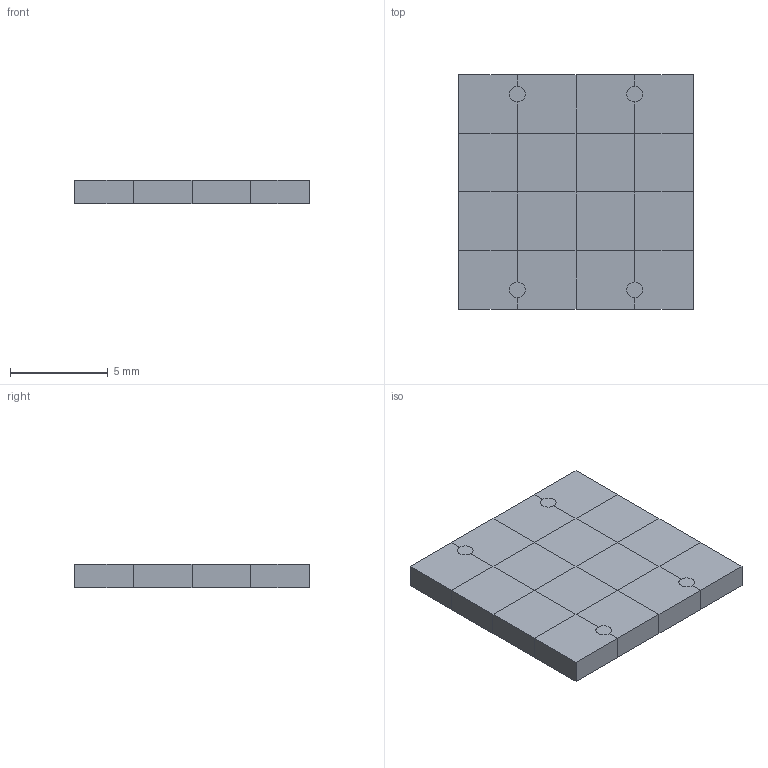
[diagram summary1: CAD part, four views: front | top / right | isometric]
STEP (ISO 10303-21) file: header records copied from the file, then geometry measured from it (millimetres).
FILE_DESCRIPTION(('Open CASCADE Model'),'2;1');
FILE_NAME('Open CASCADE Shape Model','2026-11-20T12:54:42',('Author'),( 'Open CASCADE'),'Open CASCADE STEP processor 7.9','Open CASCADE 7.9' ,'Unknown');
FILE_SCHEMA(('AUTOMOTIVE_DESIGN { 1 0 10303 214 1 1 1 1 }'));
Length unit declared in the file: millimetre
Products named in the file (3): manifold_AD_13-14_2; fluid; solid
Assembly tree (2 placements, depth 2):
  manifold_AD_13-14_2
    fluid
    solid
Bounding box: 12 x 12 x 1.2 mm (x, y, z)
Volume: 172.8 mm3; surface area: 1521.5 mm2
Topology: 2 solids, 2 shells, 1568 faces, 5808 edges, 3138 vertices
Faces by surface type: plane 1560, cylinder 8
Full cylindrical faces by diameter (mm): 0.8 x8
Entity records: 135214 total; most frequent: CARTESIAN_POINT 22181, DIRECTION 20582, LINE 17376, VECTOR 17376, ORIENTED_EDGE 11616, PCURVE 11616, DEFINITIONAL_REPRESENTATION 11616, EDGE_CURVE 5808
One B-rep face of a CAD part: STEP entity #72534.
In plain terms, the planar face has unit normal (0, 0, 1).
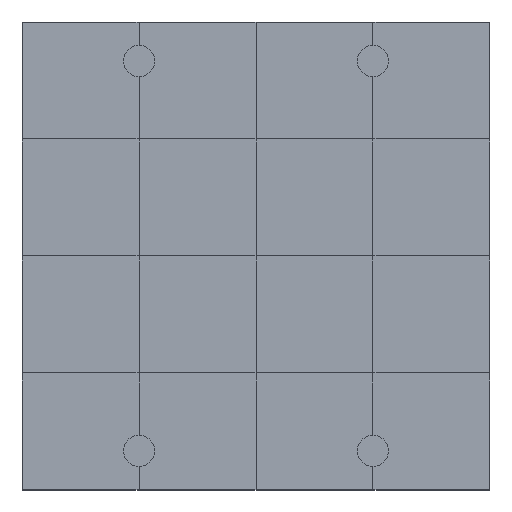
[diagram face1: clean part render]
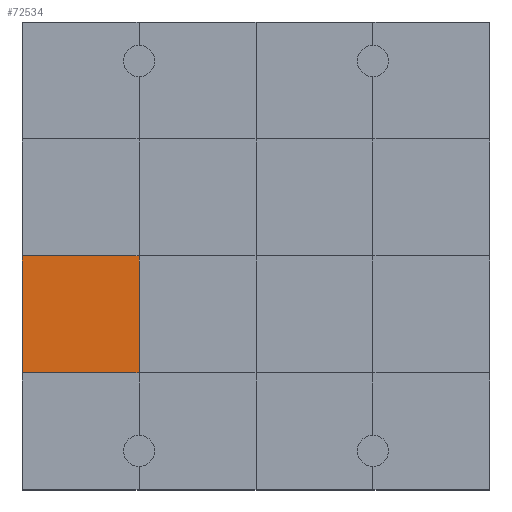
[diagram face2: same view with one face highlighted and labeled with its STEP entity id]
Its self-contained STEP definition (entity closure, numbers rounded to 3 decimals):
#72084 = VERTEX_POINT('',#72085);
#72085 = CARTESIAN_POINT('',(0.,3.,1.2));
#72099 = PLANE('',#72100);
#72100 = AXIS2_PLACEMENT_3D('',#72101,#72102,#72103);
#72101 = CARTESIAN_POINT('',(0.,3.,0.));
#72102 = DIRECTION('',(1.,0.,-0.));
#72103 = DIRECTION('',(0.,0.,1.));
#72125 = PLANE('',#72126);
#72126 = AXIS2_PLACEMENT_3D('',#72127,#72128,#72129);
#72127 = CARTESIAN_POINT('',(0.,0.,1.2));
#72128 = DIRECTION('',(0.,0.,1.));
#72129 = DIRECTION('',(1.,0.,-0.));
#72276 = VERTEX_POINT('',#72277);
#72277 = CARTESIAN_POINT('',(3.,3.,1.2));
#72298 = EDGE_CURVE('',#72084,#72276,#72299,.T.);
#72299 = SURFACE_CURVE('',#72300,(#72304,#72311),.PCURVE_S1.);
#72300 = LINE('',#72301,#72302);
#72301 = CARTESIAN_POINT('',(0.,3.,1.2));
#72302 = VECTOR('',#72303,1.);
#72303 = DIRECTION('',(1.,0.,-0.));
#72304 = PCURVE('',#72125,#72305);
#72305 = DEFINITIONAL_REPRESENTATION('',(#72306),#72310);
#72306 = LINE('',#72307,#72308);
#72307 = CARTESIAN_POINT('',(0.,3.));
#72308 = VECTOR('',#72309,1.);
#72309 = DIRECTION('',(1.,0.));
#72310 = ( GEOMETRIC_REPRESENTATION_CONTEXT(2) 
PARAMETRIC_REPRESENTATION_CONTEXT() REPRESENTATION_CONTEXT('2D SPACE',''
  ) );
#72311 = PCURVE('',#72312,#72317);
#72312 = PLANE('',#72313);
#72313 = AXIS2_PLACEMENT_3D('',#72314,#72315,#72316);
#72314 = CARTESIAN_POINT('',(0.,3.,1.2));
#72315 = DIRECTION('',(0.,0.,1.));
#72316 = DIRECTION('',(1.,0.,-0.));
#72317 = DEFINITIONAL_REPRESENTATION('',(#72318),#72322);
#72318 = LINE('',#72319,#72320);
#72319 = CARTESIAN_POINT('',(0.,0.));
#72320 = VECTOR('',#72321,1.);
#72321 = DIRECTION('',(1.,0.));
#72322 = ( GEOMETRIC_REPRESENTATION_CONTEXT(2) 
PARAMETRIC_REPRESENTATION_CONTEXT() REPRESENTATION_CONTEXT('2D SPACE',''
  ) );
#72357 = VERTEX_POINT('',#72358);
#72358 = CARTESIAN_POINT('',(0.,6.,1.2));
#72384 = EDGE_CURVE('',#72084,#72357,#72385,.T.);
#72385 = SURFACE_CURVE('',#72386,(#72390,#72397),.PCURVE_S1.);
#72386 = LINE('',#72387,#72388);
#72387 = CARTESIAN_POINT('',(0.,3.,1.2));
#72388 = VECTOR('',#72389,1.);
#72389 = DIRECTION('',(-0.,1.,0.));
#72390 = PCURVE('',#72099,#72391);
#72391 = DEFINITIONAL_REPRESENTATION('',(#72392),#72396);
#72392 = LINE('',#72393,#72394);
#72393 = CARTESIAN_POINT('',(1.2,0.));
#72394 = VECTOR('',#72395,1.);
#72395 = DIRECTION('',(0.,-1.));
#72396 = ( GEOMETRIC_REPRESENTATION_CONTEXT(2) 
PARAMETRIC_REPRESENTATION_CONTEXT() REPRESENTATION_CONTEXT('2D SPACE',''
  ) );
#72397 = PCURVE('',#72312,#72398);
#72398 = DEFINITIONAL_REPRESENTATION('',(#72399),#72403);
#72399 = LINE('',#72400,#72401);
#72400 = CARTESIAN_POINT('',(0.,0.));
#72401 = VECTOR('',#72402,1.);
#72402 = DIRECTION('',(0.,1.));
#72403 = ( GEOMETRIC_REPRESENTATION_CONTEXT(2) 
PARAMETRIC_REPRESENTATION_CONTEXT() REPRESENTATION_CONTEXT('2D SPACE',''
  ) );
#72534 = ADVANCED_FACE('',(#72535),#72312,.T.);
#72535 = FACE_BOUND('',#72536,.T.);
#72536 = EDGE_LOOP('',(#72537,#72538,#72539,#72567));
#72537 = ORIENTED_EDGE('',*,*,#72384,.F.);
#72538 = ORIENTED_EDGE('',*,*,#72298,.T.);
#72539 = ORIENTED_EDGE('',*,*,#72540,.T.);
#72540 = EDGE_CURVE('',#72276,#72541,#72543,.T.);
#72541 = VERTEX_POINT('',#72542);
#72542 = CARTESIAN_POINT('',(3.,6.,1.2));
#72543 = SURFACE_CURVE('',#72544,(#72548,#72555),.PCURVE_S1.);
#72544 = LINE('',#72545,#72546);
#72545 = CARTESIAN_POINT('',(3.,3.,1.2));
#72546 = VECTOR('',#72547,1.);
#72547 = DIRECTION('',(-0.,1.,0.));
#72548 = PCURVE('',#72312,#72549);
#72549 = DEFINITIONAL_REPRESENTATION('',(#72550),#72554);
#72550 = LINE('',#72551,#72552);
#72551 = CARTESIAN_POINT('',(3.,0.));
#72552 = VECTOR('',#72553,1.);
#72553 = DIRECTION('',(0.,1.));
#72554 = ( GEOMETRIC_REPRESENTATION_CONTEXT(2) 
PARAMETRIC_REPRESENTATION_CONTEXT() REPRESENTATION_CONTEXT('2D SPACE',''
  ) );
#72555 = PCURVE('',#72556,#72561);
#72556 = PLANE('',#72557);
#72557 = AXIS2_PLACEMENT_3D('',#72558,#72559,#72560);
#72558 = CARTESIAN_POINT('',(3.,3.,1.2));
#72559 = DIRECTION('',(0.,0.,1.));
#72560 = DIRECTION('',(1.,0.,-0.));
#72561 = DEFINITIONAL_REPRESENTATION('',(#72562),#72566);
#72562 = LINE('',#72563,#72564);
#72563 = CARTESIAN_POINT('',(0.,0.));
#72564 = VECTOR('',#72565,1.);
#72565 = DIRECTION('',(0.,1.));
#72566 = ( GEOMETRIC_REPRESENTATION_CONTEXT(2) 
PARAMETRIC_REPRESENTATION_CONTEXT() REPRESENTATION_CONTEXT('2D SPACE',''
  ) );
#72567 = ORIENTED_EDGE('',*,*,#72568,.F.);
#72568 = EDGE_CURVE('',#72357,#72541,#72569,.T.);
#72569 = SURFACE_CURVE('',#72570,(#72574,#72581),.PCURVE_S1.);
#72570 = LINE('',#72571,#72572);
#72571 = CARTESIAN_POINT('',(0.,6.,1.2));
#72572 = VECTOR('',#72573,1.);
#72573 = DIRECTION('',(1.,0.,-0.));
#72574 = PCURVE('',#72312,#72575);
#72575 = DEFINITIONAL_REPRESENTATION('',(#72576),#72580);
#72576 = LINE('',#72577,#72578);
#72577 = CARTESIAN_POINT('',(0.,3.));
#72578 = VECTOR('',#72579,1.);
#72579 = DIRECTION('',(1.,0.));
#72580 = ( GEOMETRIC_REPRESENTATION_CONTEXT(2) 
PARAMETRIC_REPRESENTATION_CONTEXT() REPRESENTATION_CONTEXT('2D SPACE',''
  ) );
#72581 = PCURVE('',#72582,#72587);
#72582 = PLANE('',#72583);
#72583 = AXIS2_PLACEMENT_3D('',#72584,#72585,#72586);
#72584 = CARTESIAN_POINT('',(0.,6.,1.2));
#72585 = DIRECTION('',(0.,0.,1.));
#72586 = DIRECTION('',(1.,0.,-0.));
#72587 = DEFINITIONAL_REPRESENTATION('',(#72588),#72592);
#72588 = LINE('',#72589,#72590);
#72589 = CARTESIAN_POINT('',(0.,0.));
#72590 = VECTOR('',#72591,1.);
#72591 = DIRECTION('',(1.,0.));
#72592 = ( GEOMETRIC_REPRESENTATION_CONTEXT(2) 
PARAMETRIC_REPRESENTATION_CONTEXT() REPRESENTATION_CONTEXT('2D SPACE',''
  ) );
